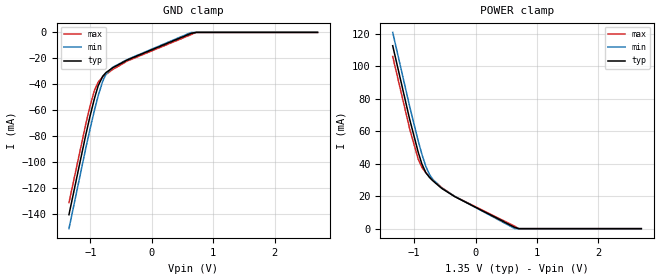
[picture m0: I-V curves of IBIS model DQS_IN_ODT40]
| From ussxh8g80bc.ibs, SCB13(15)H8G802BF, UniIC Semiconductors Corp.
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| MODEL DQS_IN_ODT40 (Data Strobe Input with 40ohm ODT, 800-2133Mbps)
[Model]   DQS_IN_ODT40
Model_type   Input
Vinl = 545.000mV
Vinh = 805.000mV
|   typ   min   max
|C_comp   1.076pF   1.020pF   1.111pF
C_comp_power_clamp   0.5380pF   0.5100pF   0.5555pF
C_comp_gnd_clamp   0.5380pF   0.5100pF   0.5555pF
| Note: C_comp changes when the ODT circuit is enabled.
[Model Spec]
| Input threshold voltage corners
Vinl   0.5450V   0.5115V   0.5825V
Vinh   0.8050V   0.7715V   0.8425V
| Dynamic Overshoot Parameters from DDR3L Specification
|D_overshoot_ampl_h   0.40   NA   NA
|D_overshoot_ampl_l   0.40   NA   NA
|D_overshoot_area_h   0.11n   NA   NA
|D_overshoot_area_l   0.11n   NA   NA
[Receiver Thresholds]
|Vth   =  0.675V
|Vth_min  =  0.6615V
|Vth_max  =  0.6885V
|Vinh_ac  =  0.130V
|Vinh_dc  =  0.090V
|Vinl_ac  = -0.130V
|Vinl_dc  = -0.090V
|Tslew_ac =  5.000ns |Not specified, so set to high value
|Threshold_sensitivity = 0.50
|Reference_supply Power_clamp_ref
|NOTE: If using the IBISCHK 4.2.1 or older parser, Differential receiver
|threshold parameters must be commented out because the parser generates
|errors for multiple differential models.
Vcross_low   = 0.545V
Vcross_high  = 0.805V
Vdiff_ac   = 260mV
Vdiff_dc   = 180mV
Tdiffslew_ac = 10.000ns |Not specified, so set to high value
[Voltage Range]   1.3500V   1.2830V   1.4250V
[POWER Clamp Reference]   1.3500V   1.2830V   1.4250V
| Junction Temperature (Ambient temp is 40C typ, 85C min, 0C max)
[Temperature Range]   45.0   90.0   0.0
[GND Clamp]
|   Voltage   I(typ)   I(min)   I(max)
-1.35V    -140.6mA   -151.4mA   -131.4mA
-1.075V   -78.79mA   -89.12mA   -70.46mA
-1.005V   -64.28mA   -74.23mA   -56.57mA
-935mV    -51mA      -60.09mA   -44.75mA
-875mV    -41.28mA   -49.01mA   -38.43mA
-800mV    -33.8mA    -37.59mA   -34.26mA
-745mV    -30.93mA   -32.17mA   -32.27mA
-640mV    -27.38mA   -26.98mA   -28.74mA
-400mV    -21.26mA   -20.92mA   -22.09mA
640mV     -769.1uA   -43.14uA   -1.721mA
720mV     0A         0A         0A
2.7V      0A         0A         0A
[POWER Clamp]
|   Voltage   I(typ)   I(min)   I(max)
-1.35V    112.5mA    120.7mA    105.9mA
-1.075V   67.44mA    75.32mA    61.57mA
-935mV    47.05mA    54.01mA    42.78mA
-875mV    39.82mA    45.82mA    37.75mA
-810mV    34.41mA    38.26mA    34.36mA
-750mV    31.45mA    33.22mA    32.04mA
-690mV    29.22mA    29.94mA    29.9mA
-550mV    24.74mA    24.87mA    25.23mA
-340mV    19.7mA     19.9mA     19.86mA
640mV     765.8uA    22.39uA    1.435mA
705mV     0A         0A         0A
2.7V      0A         0A         0A
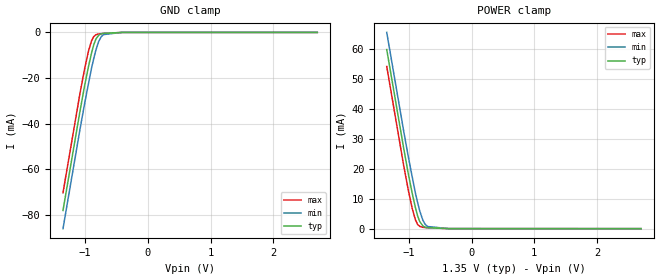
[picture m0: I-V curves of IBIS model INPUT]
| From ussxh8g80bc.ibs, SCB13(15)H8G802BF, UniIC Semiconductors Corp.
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| MODEL INPUT (Add/Cmd/Ctrl Input Model, 800-2133Mbps)
[Model]   INPUT
Model_type   Input
Vinl = 550.000mV
Vinh = 800.000mV
|   typ   min   max
|C_comp   0.550pF   0.500pF   0.600pF
C_comp_power_clamp   0.2750pF   0.2500pF   0.3000pF
C_comp_gnd_clamp   0.2750pF   0.2500pF   0.3000pF
[Model Spec]
| Input threshold voltage corners
Vinl   0.5500V   0.5165V   0.5875V
Vinh   0.8000V   0.7665V   0.8375V
| Dynamic Overshoot Parameters from DDR3L Specification
|D_overshoot_ampl_h   0.40   NA   NA
|D_overshoot_ampl_l   0.40   NA   NA
|D_overshoot_area_h   0.28n   NA   NA
|D_overshoot_area_l   0.28n   NA   NA
[Receiver Thresholds]
Vth   =  0.675V
Vth_min  =  0.6615V
Vth_max  =  0.6885V
Vinh_ac  =  0.125V
Vinh_dc  =  0.090V
Vinl_ac  = -0.125V
Vinl_dc  = -0.090V
Tslew_ac =  5.000ns |Not specified, so set to high value
Threshold_sensitivity = 0.50
Reference_supply Power_clamp_ref
[Voltage Range]   1.3500V   1.2830V   1.4250V
[POWER Clamp Reference]   1.3500V   1.2830V   1.4250V
| Junction Temperature (Ambient temp is 40C typ, 85C min, 0C max)
[Temperature Range]   45.0   90.0   0.0
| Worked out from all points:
|   GND clamp passes 1 mA (typ) near -0.77 V on its own axis
|   POWER clamp passes 1 mA (typ) near -0.78 V on its own axis
[GND Clamp]
|   Voltage   I(typ)   I(min)   I(max)
-1.35V    -77.94mA   -85.9mA    -70.2mA
-1.08V    -34.61mA   -42.55mA   -26.76mA
-1.005V   -23.24mA   -31.09mA   -15.88mA
-945mV    -15.06mA   -22.55mA   -8.308mA
-895mV    -8.972mA   -15.61mA   -3.645mA
-860mV    -5.405mA   -11.43mA   -1.791mA
-825mV    -2.863mA   -7.627mA   -1.006mA
-780mV    -1.216mA   -3.852mA   -673.7uA
-740mV    -621.9uA   -1.855mA   -548.1uA
-705mV    -421.4uA   -971uA     -464.6uA
-415mV    -19.61uA   -10.04uA   -32.28uA
2.7V      0A         0A         0A
[POWER Clamp]
|   Voltage   I(typ)   I(min)   I(max)
-1.35V    59.7mA     65.43mA    54.08mA
-1.08V    26.78mA    32.51mA    21.02mA
-1.005V   18.11mA    23.81mA    12.67mA
-945mV    11.86mA    17.32mA    6.789mA
-895mV    7.168mA    12.04mA    3.042mA
-860mV    4.389mA    8.853mA    1.461mA
-825mV    2.363mA    5.945mA    759.5uA
-775mV    933.4uA    2.834mA    457.8uA
-740mV    498.7uA    1.498mA    381.2uA
-700mV    313.6uA    721.7uA    319.5uA
-365mV    12.84uA    7.66uA     15.57uA
2.7V      0A         0A         0A
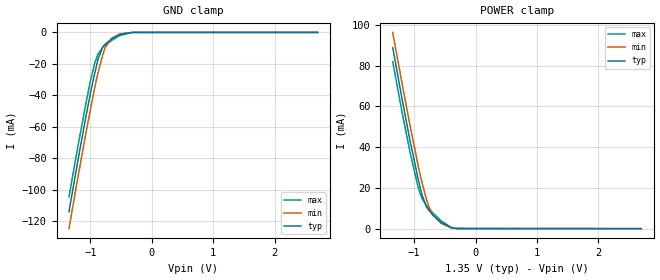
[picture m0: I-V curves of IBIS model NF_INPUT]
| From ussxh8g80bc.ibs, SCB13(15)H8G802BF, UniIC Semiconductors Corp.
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| MODEL NF_INPUT (Non-Functioning Terminator Model)
[Model]   NF_INPUT
Model_type   Terminator
|   typ   min   max
|C_comp   0.950pF   0.900pF   1.000pF
C_comp_power_clamp   0.4750pF   0.4500pF   0.5000pF
C_comp_gnd_clamp   0.4750pF   0.4500pF   0.5000pF
[Voltage Range]   1.3500V   1.2830V   1.4250V
| Junction Temperature (Ambient temp is 40C typ, 85C min, 0C max)
[Temperature Range]   45.0   90.0   0.0
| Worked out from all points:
|   GND clamp passes 1 mA (typ) near -0.50 V on its own axis
|   POWER clamp passes 1 mA (typ) near -0.45 V on its own axis
[GND Clamp]
|   Voltage   I(typ)   I(min)   I(max)
-1.35V    -113.9mA   -124.6mA   -104.5mA
-1.205V   -81.48mA   -92.16mA   -72.46mA
-1.07V    -52.65mA   -63.14mA   -44.3mA
-1V       -38.7mA    -48.81mA   -30.85mA
-930mV    -25.95mA   -35.02mA   -19.4mA
-875mV    -16.88mA   -25.36mA   -13.69mA
-800mV    -9.222mA   -14.41mA   -9.487mA
-765mV    -7.604mA   -9.974mA   -8.359mA
-650mV    -3.918mA   -3.687mA   -5.017mA
-520mV    -1.303mA   -937.1uA   -1.955mA
-315mV    -19.67uA   -18.79uA   -28.64uA
2.7V      0A         0A         0A
[POWER Clamp]
|   Voltage   I(typ)   I(min)   I(max)
-1.35V    88.89mA    96.37mA    82.02mA
-1.205V   64.87mA    72.5mA     58.31mA
-1.07V    43.46mA    51mA       37.77mA
-930mV    23.58mA    30.09mA    19.57mA
-875mV    16.77mA    22.82mA    15.04mA
-800mV    10.68mA    14.43mA    11.22mA
-765mV    9.147mA    10.97mA    10.01mA
-690mV    6.433mA    6.617mA    7.571mA
-565mV    3.162mA    2.653mA    3.926mA
-395mV    485.8uA    358.5uA    537uA
-310mV    60.31uA    60.42uA    66.72uA
2.7V      0A         0A         0A
